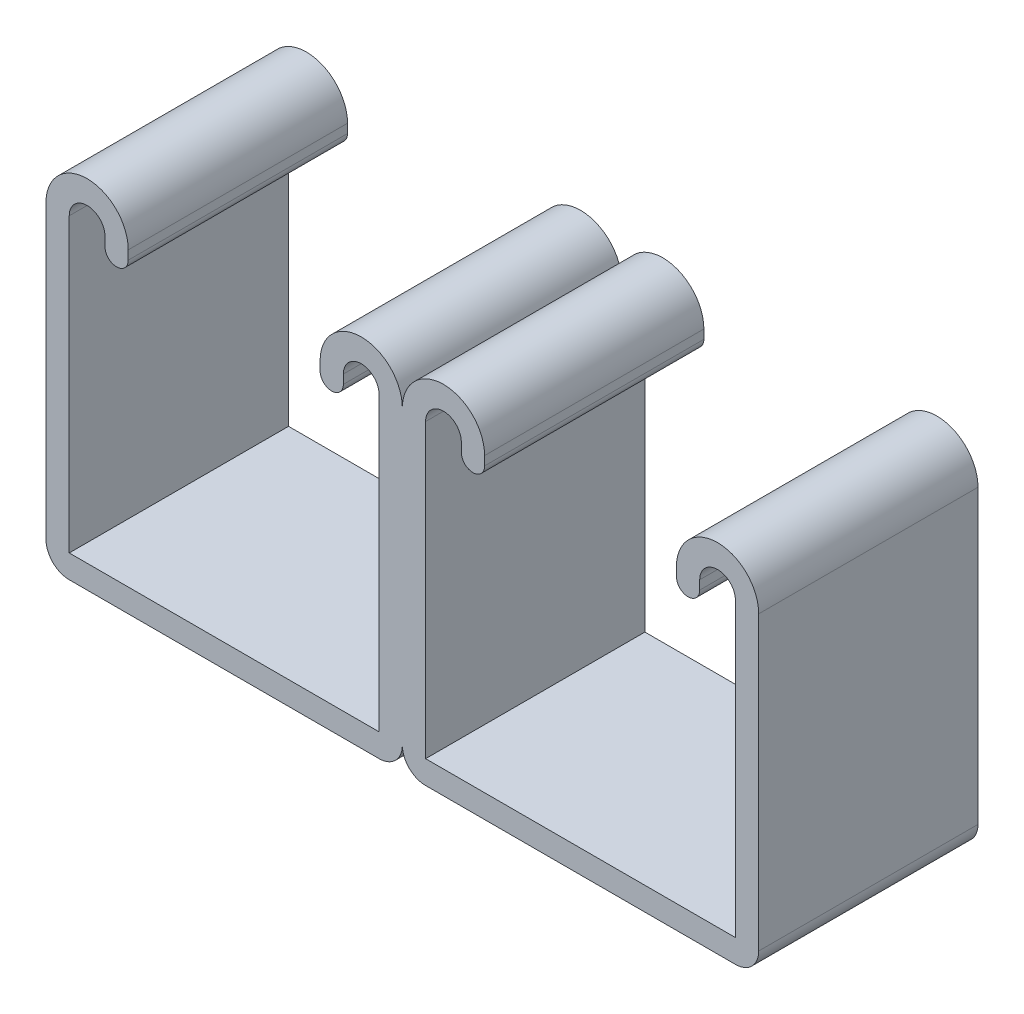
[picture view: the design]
ISO-10303-21;
HEADER;
FILE_DESCRIPTION(('STEP AP214'),'2;1');
FILE_NAME('part.step','',(''),(''),'','','');
FILE_SCHEMA(('AUTOMOTIVE_DESIGN { 1 0 10303 214 1 1 1 1 }'));
ENDSEC;
DATA;
#1=APPLICATION_CONTEXT('core data for automotive mechanical design processes');
#2=APPLICATION_PROTOCOL_DEFINITION('international standard','automotive_design',2000,#1);
#3=PRODUCT_CONTEXT('',#1,'mechanical');
#4=PRODUCT('Part','Part','',(#3));
#5=PRODUCT_RELATED_PRODUCT_CATEGORY('part','',(#4));
#6=PRODUCT_DEFINITION_FORMATION('','',#4);
#7=PRODUCT_DEFINITION_CONTEXT('part definition',#1,'design');
#8=PRODUCT_DEFINITION('design','',#6,#7);
#9=PRODUCT_DEFINITION_SHAPE('','',#8);
#10=(LENGTH_UNIT() NAMED_UNIT(*) SI_UNIT(.MILLI.,.METRE.));
#11=(NAMED_UNIT(*) PLANE_ANGLE_UNIT() SI_UNIT($,.RADIAN.));
#12=(NAMED_UNIT(*) SI_UNIT($,.STERADIAN.) SOLID_ANGLE_UNIT());
#13=UNCERTAINTY_MEASURE_WITH_UNIT(LENGTH_MEASURE(1.E-05),#10,'distance_accuracy_value','');
#14=(GEOMETRIC_REPRESENTATION_CONTEXT(3) GLOBAL_UNCERTAINTY_ASSIGNED_CONTEXT((#13)) GLOBAL_UNIT_ASSIGNED_CONTEXT((#10,
#11,#12)) REPRESENTATION_CONTEXT('',''));
#15=CARTESIAN_POINT('',(0.,0.,0.));
#16=DIRECTION('',(0.,0.,1.));
#17=DIRECTION('',(1.,0.,0.));
#18=AXIS2_PLACEMENT_3D('',#15,#16,#17);
#19=CARTESIAN_POINT('',(-36.5125,18.4785,12.7));
#20=DIRECTION('',(0.,0.,-1.));
#21=DIRECTION('',(-1.,0.,0.));
#22=AXIS2_PLACEMENT_3D('',#19,#20,#21);
#23=CYLINDRICAL_SURFACE('',#22,4.7625);
#24=CARTESIAN_POINT('',(-36.5125,18.4785,-12.7));
#25=DIRECTION('',(0.,0.,1.));
#26=DIRECTION('',(-1.,0.,0.));
#27=AXIS2_PLACEMENT_3D('',#24,#25,#26);
#28=CIRCLE('',#27,4.7625);
#29=CARTESIAN_POINT('',(-31.75,18.4785,-12.7));
#30=VERTEX_POINT('',#29);
#31=CARTESIAN_POINT('',(-41.275,18.4785,-12.7));
#32=VERTEX_POINT('',#31);
#33=EDGE_CURVE('E190',#30,#32,#28,.T.);
#34=ORIENTED_EDGE('',*,*,#33,.T.);
#35=DIRECTION('',(0.,0.,-1.));
#36=VECTOR('',#35,1.);
#37=CARTESIAN_POINT('',(-41.275,18.4785,12.7));
#38=LINE('',#37,#36);
#39=CARTESIAN_POINT('',(-41.275,18.4785,12.7));
#40=VERTEX_POINT('',#39);
#41=EDGE_CURVE('E11',#40,#32,#38,.T.);
#42=ORIENTED_EDGE('',*,*,#41,.F.);
#43=CARTESIAN_POINT('',(-36.5125,18.4785,12.7));
#44=DIRECTION('',(0.,0.,1.));
#45=DIRECTION('',(-1.,0.,0.));
#46=AXIS2_PLACEMENT_3D('',#43,#44,#45);
#47=CIRCLE('',#46,4.7625);
#48=CARTESIAN_POINT('',(-31.75,18.4785,12.7));
#49=VERTEX_POINT('',#48);
#50=EDGE_CURVE('E223',#49,#40,#47,.T.);
#51=ORIENTED_EDGE('',*,*,#50,.F.);
#52=DIRECTION('',(0.,0.,-1.));
#53=VECTOR('',#52,1.);
#54=CARTESIAN_POINT('',(-31.75,18.4785,12.7));
#55=LINE('',#54,#53);
#56=EDGE_CURVE('E186',#49,#30,#55,.T.);
#57=ORIENTED_EDGE('',*,*,#56,.T.);
#58=EDGE_LOOP('',(#34,#42,#51,#57));
#59=FACE_BOUND('',#58,.T.);
#60=ADVANCED_FACE('F33',(#59),#23,.T.);
#61=CARTESIAN_POINT('',(-41.275,18.4785,12.7));
#62=DIRECTION('',(1.,0.,0.));
#63=DIRECTION('',(0.,1.,0.));
#64=AXIS2_PLACEMENT_3D('',#61,#62,#63);
#65=PLANE('',#64);
#66=DIRECTION('',(0.,-1.,0.));
#67=VECTOR('',#66,1.);
#68=CARTESIAN_POINT('',(-41.275,18.4785,-12.7));
#69=LINE('',#68,#67);
#70=CARTESIAN_POINT('',(-41.275,-15.3416,-12.7));
#71=VERTEX_POINT('',#70);
#72=EDGE_CURVE('E193',#32,#71,#69,.T.);
#73=ORIENTED_EDGE('',*,*,#72,.T.);
#74=DIRECTION('',(0.,0.,-1.));
#75=VECTOR('',#74,1.);
#76=CARTESIAN_POINT('',(-41.275,-15.3416,12.7));
#77=LINE('',#76,#75);
#78=CARTESIAN_POINT('',(-41.275,-15.3416,12.7));
#79=VERTEX_POINT('',#78);
#80=EDGE_CURVE('E41',#79,#71,#77,.T.);
#81=ORIENTED_EDGE('',*,*,#80,.F.);
#82=DIRECTION('',(0.,-1.,0.));
#83=VECTOR('',#82,1.);
#84=CARTESIAN_POINT('',(-41.275,18.4785,12.7));
#85=LINE('',#84,#83);
#86=EDGE_CURVE('E120',#40,#79,#85,.T.);
#87=ORIENTED_EDGE('',*,*,#86,.F.);
#88=ORIENTED_EDGE('',*,*,#41,.T.);
#89=EDGE_LOOP('',(#73,#81,#87,#88));
#90=FACE_BOUND('',#89,.T.);
#91=ADVANCED_FACE('F330',(#90),#65,.F.);
#92=CARTESIAN_POINT('',(-38.5826,-15.3416,12.7));
#93=DIRECTION('',(0.,0.,-1.));
#94=DIRECTION('',(-1.,0.,0.));
#95=AXIS2_PLACEMENT_3D('',#92,#93,#94);
#96=CYLINDRICAL_SURFACE('',#95,2.6924);
#97=CARTESIAN_POINT('',(-38.5826,-15.3416,-12.7));
#98=DIRECTION('',(0.,0.,1.));
#99=DIRECTION('',(-1.,0.,0.));
#100=AXIS2_PLACEMENT_3D('',#97,#98,#99);
#101=CIRCLE('',#100,2.6924);
#102=CARTESIAN_POINT('',(-38.5826,-18.034,-12.7));
#103=VERTEX_POINT('',#102);
#104=EDGE_CURVE('E196',#71,#103,#101,.T.);
#105=ORIENTED_EDGE('',*,*,#104,.T.);
#106=DIRECTION('',(0.,0.,-1.));
#107=VECTOR('',#106,1.);
#108=CARTESIAN_POINT('',(-38.5826,-18.034,12.7));
#109=LINE('',#108,#107);
#110=CARTESIAN_POINT('',(-38.5826,-18.034,12.7));
#111=VERTEX_POINT('',#110);
#112=EDGE_CURVE('E260',#111,#103,#109,.T.);
#113=ORIENTED_EDGE('',*,*,#112,.F.);
#114=CARTESIAN_POINT('',(-38.5826,-15.3416,12.7));
#115=DIRECTION('',(0.,0.,1.));
#116=DIRECTION('',(-1.,0.,0.));
#117=AXIS2_PLACEMENT_3D('',#114,#115,#116);
#118=CIRCLE('',#117,2.6924);
#119=EDGE_CURVE('E268',#79,#111,#118,.T.);
#120=ORIENTED_EDGE('',*,*,#119,.F.);
#121=ORIENTED_EDGE('',*,*,#80,.T.);
#122=EDGE_LOOP('',(#105,#113,#120,#121));
#123=FACE_BOUND('',#122,.T.);
#124=ADVANCED_FACE('F266',(#123),#96,.T.);
#125=CARTESIAN_POINT('',(-38.5826,-18.034,12.7));
#126=DIRECTION('',(0.,1.,0.));
#127=DIRECTION('',(0.,0.,1.));
#128=AXIS2_PLACEMENT_3D('',#125,#126,#127);
#129=PLANE('',#128);
#130=DIRECTION('',(1.,0.,0.));
#131=VECTOR('',#130,1.);
#132=CARTESIAN_POINT('',(-38.5826,-18.034,-12.7));
#133=LINE('',#132,#131);
#134=CARTESIAN_POINT('',(-2.6924,-18.034,-12.7));
#135=VERTEX_POINT('',#134);
#136=EDGE_CURVE('E198',#103,#135,#133,.T.);
#137=ORIENTED_EDGE('',*,*,#136,.T.);
#138=DIRECTION('',(0.,0.,-1.));
#139=VECTOR('',#138,1.);
#140=CARTESIAN_POINT('',(-2.6924,-18.034,12.7));
#141=LINE('',#140,#139);
#142=CARTESIAN_POINT('',(-2.6924,-18.034,12.7));
#143=VERTEX_POINT('',#142);
#144=EDGE_CURVE('E257',#143,#135,#141,.T.);
#145=ORIENTED_EDGE('',*,*,#144,.F.);
#146=DIRECTION('',(1.,0.,0.));
#147=VECTOR('',#146,1.);
#148=CARTESIAN_POINT('',(-38.5826,-18.034,12.7));
#149=LINE('',#148,#147);
#150=EDGE_CURVE('E287',#111,#143,#149,.T.);
#151=ORIENTED_EDGE('',*,*,#150,.F.);
#152=ORIENTED_EDGE('',*,*,#112,.T.);
#153=EDGE_LOOP('',(#137,#145,#151,#152));
#154=FACE_BOUND('',#153,.T.);
#155=ADVANCED_FACE('F277',(#154),#129,.F.);
#156=CARTESIAN_POINT('',(-2.6924,-15.3416,12.7));
#157=DIRECTION('',(0.,0.,-1.));
#158=DIRECTION('',(-1.,0.,0.));
#159=AXIS2_PLACEMENT_3D('',#156,#157,#158);
#160=CYLINDRICAL_SURFACE('',#159,2.6924);
#161=CARTESIAN_POINT('',(-2.6924,-15.3416,-12.7));
#162=DIRECTION('',(0.,0.,1.));
#163=DIRECTION('',(1.,0.,0.));
#164=AXIS2_PLACEMENT_3D('',#161,#162,#163);
#165=CIRCLE('',#164,2.6924);
#166=CARTESIAN_POINT('',(0.,-15.3416,-12.7));
#167=VERTEX_POINT('',#166);
#168=EDGE_CURVE('E200',#135,#167,#165,.T.);
#169=ORIENTED_EDGE('',*,*,#168,.T.);
#170=DIRECTION('',(0.,0.,-1.));
#171=VECTOR('',#170,1.);
#172=CARTESIAN_POINT('',(0.,-15.3416,12.7));
#173=LINE('',#172,#171);
#174=CARTESIAN_POINT('',(0.,-15.3416,12.7));
#175=VERTEX_POINT('',#174);
#176=EDGE_CURVE('E254',#175,#167,#173,.T.);
#177=ORIENTED_EDGE('',*,*,#176,.F.);
#178=CARTESIAN_POINT('',(-2.6924,-15.3416,12.7));
#179=DIRECTION('',(0.,0.,1.));
#180=DIRECTION('',(1.,0.,0.));
#181=AXIS2_PLACEMENT_3D('',#178,#179,#180);
#182=CIRCLE('',#181,2.6924);
#183=EDGE_CURVE('E283',#143,#175,#182,.T.);
#184=ORIENTED_EDGE('',*,*,#183,.F.);
#185=ORIENTED_EDGE('',*,*,#144,.T.);
#186=EDGE_LOOP('',(#169,#177,#184,#185));
#187=FACE_BOUND('',#186,.T.);
#188=ADVANCED_FACE('F281',(#187),#160,.T.);
#189=CARTESIAN_POINT('',(-4.7625,18.4785,12.7));
#190=DIRECTION('',(0.,0.,-1.));
#191=DIRECTION('',(-1.,0.,0.));
#192=AXIS2_PLACEMENT_3D('',#189,#190,#191);
#193=CYLINDRICAL_SURFACE('',#192,4.7625);
#194=CARTESIAN_POINT('',(-4.7625,18.4785,-12.7));
#195=DIRECTION('',(0.,0.,1.));
#196=DIRECTION('',(1.,0.,0.));
#197=AXIS2_PLACEMENT_3D('',#194,#195,#196);
#198=CIRCLE('',#197,4.7625);
#199=CARTESIAN_POINT('',(0.,18.4785,-12.7));
#200=VERTEX_POINT('',#199);
#201=CARTESIAN_POINT('',(-9.525,18.4785,-12.7));
#202=VERTEX_POINT('',#201);
#203=EDGE_CURVE('E202',#200,#202,#198,.T.);
#204=ORIENTED_EDGE('',*,*,#203,.T.);
#205=DIRECTION('',(0.,0.,-1.));
#206=VECTOR('',#205,1.);
#207=CARTESIAN_POINT('',(-9.525,18.4785,12.7));
#208=LINE('',#207,#206);
#209=CARTESIAN_POINT('',(-9.525,18.4785,12.7));
#210=VERTEX_POINT('',#209);
#211=EDGE_CURVE('E248',#210,#202,#208,.T.);
#212=ORIENTED_EDGE('',*,*,#211,.F.);
#213=CARTESIAN_POINT('',(-4.7625,18.4785,12.7));
#214=DIRECTION('',(0.,0.,1.));
#215=DIRECTION('',(1.,0.,0.));
#216=AXIS2_PLACEMENT_3D('',#213,#214,#215);
#217=CIRCLE('',#216,4.7625);
#218=CARTESIAN_POINT('',(0.,18.4785,12.7));
#219=VERTEX_POINT('',#218);
#220=EDGE_CURVE('E286',#219,#210,#217,.T.);
#221=ORIENTED_EDGE('',*,*,#220,.F.);
#222=DIRECTION('',(0.,0.,-1.));
#223=VECTOR('',#222,1.);
#224=CARTESIAN_POINT('',(0.,18.4785,12.7));
#225=LINE('',#224,#223);
#226=EDGE_CURVE('E251',#219,#200,#225,.T.);
#227=ORIENTED_EDGE('',*,*,#226,.T.);
#228=EDGE_LOOP('',(#204,#212,#221,#227));
#229=FACE_BOUND('',#228,.T.);
#230=ADVANCED_FACE('F343',(#229),#193,.T.);
#231=CARTESIAN_POINT('',(-9.525,18.4785,12.7));
#232=DIRECTION('',(1.,0.,0.));
#233=DIRECTION('',(0.,1.,0.));
#234=AXIS2_PLACEMENT_3D('',#231,#232,#233);
#235=PLANE('',#234);
#236=DIRECTION('',(0.,-1.,0.));
#237=VECTOR('',#236,1.);
#238=CARTESIAN_POINT('',(-9.525,18.4785,-12.7));
#239=LINE('',#238,#237);
#240=CARTESIAN_POINT('',(-9.525,17.44345,-12.7));
#241=VERTEX_POINT('',#240);
#242=EDGE_CURVE('E204',#202,#241,#239,.T.);
#243=ORIENTED_EDGE('',*,*,#242,.T.);
#244=DIRECTION('',(0.,0.,-1.));
#245=VECTOR('',#244,1.);
#246=CARTESIAN_POINT('',(-9.525,17.44345,12.7));
#247=LINE('',#246,#245);
#248=CARTESIAN_POINT('',(-9.525,17.44345,12.7));
#249=VERTEX_POINT('',#248);
#250=EDGE_CURVE('E245',#249,#241,#247,.T.);
#251=ORIENTED_EDGE('',*,*,#250,.F.);
#252=DIRECTION('',(0.,-1.,0.));
#253=VECTOR('',#252,1.);
#254=CARTESIAN_POINT('',(-9.525,18.4785,12.7));
#255=LINE('',#254,#253);
#256=EDGE_CURVE('E289',#210,#249,#255,.T.);
#257=ORIENTED_EDGE('',*,*,#256,.F.);
#258=ORIENTED_EDGE('',*,*,#211,.T.);
#259=EDGE_LOOP('',(#243,#251,#257,#258));
#260=FACE_BOUND('',#259,.T.);
#261=ADVANCED_FACE('F346',(#260),#235,.F.);
#262=CARTESIAN_POINT('',(-8.1788,17.44345,12.7));
#263=DIRECTION('',(0.,0.,-1.));
#264=DIRECTION('',(-1.,0.,0.));
#265=AXIS2_PLACEMENT_3D('',#262,#263,#264);
#266=CYLINDRICAL_SURFACE('',#265,1.3462);
#267=CARTESIAN_POINT('',(-8.1788,17.44345,-12.7));
#268=DIRECTION('',(0.,0.,1.));
#269=DIRECTION('',(1.,0.,0.));
#270=AXIS2_PLACEMENT_3D('',#267,#268,#269);
#271=CIRCLE('',#270,1.3462);
#272=CARTESIAN_POINT('',(-6.8326,17.44345,-12.7));
#273=VERTEX_POINT('',#272);
#274=EDGE_CURVE('E206',#241,#273,#271,.T.);
#275=ORIENTED_EDGE('',*,*,#274,.T.);
#276=DIRECTION('',(0.,0.,-1.));
#277=VECTOR('',#276,1.);
#278=CARTESIAN_POINT('',(-6.8326,17.44345,12.7));
#279=LINE('',#278,#277);
#280=CARTESIAN_POINT('',(-6.8326,17.44345,12.7));
#281=VERTEX_POINT('',#280);
#282=EDGE_CURVE('E242',#281,#273,#279,.T.);
#283=ORIENTED_EDGE('',*,*,#282,.F.);
#284=CARTESIAN_POINT('',(-8.1788,17.44345,12.7));
#285=DIRECTION('',(0.,0.,1.));
#286=DIRECTION('',(1.,0.,0.));
#287=AXIS2_PLACEMENT_3D('',#284,#285,#286);
#288=CIRCLE('',#287,1.3462);
#289=EDGE_CURVE('E295',#249,#281,#288,.T.);
#290=ORIENTED_EDGE('',*,*,#289,.F.);
#291=ORIENTED_EDGE('',*,*,#250,.T.);
#292=EDGE_LOOP('',(#275,#283,#290,#291));
#293=FACE_BOUND('',#292,.T.);
#294=ADVANCED_FACE('F350',(#293),#266,.T.);
#295=CARTESIAN_POINT('',(-6.8326,18.4785,12.7));
#296=DIRECTION('',(-1.,0.,0.));
#297=DIRECTION('',(0.,0.,1.));
#298=AXIS2_PLACEMENT_3D('',#295,#296,#297);
#299=PLANE('',#298);
#300=DIRECTION('',(0.,1.,0.));
#301=VECTOR('',#300,1.);
#302=CARTESIAN_POINT('',(-6.8326,18.4785,-12.7));
#303=LINE('',#302,#301);
#304=CARTESIAN_POINT('',(-6.8326,18.4785,-12.7));
#305=VERTEX_POINT('',#304);
#306=EDGE_CURVE('E208',#273,#305,#303,.T.);
#307=ORIENTED_EDGE('',*,*,#306,.T.);
#308=DIRECTION('',(0.,0.,-1.));
#309=VECTOR('',#308,1.);
#310=CARTESIAN_POINT('',(-6.8326,18.4785,12.7));
#311=LINE('',#310,#309);
#312=CARTESIAN_POINT('',(-6.8326,18.4785,12.7));
#313=VERTEX_POINT('',#312);
#314=EDGE_CURVE('E239',#313,#305,#311,.T.);
#315=ORIENTED_EDGE('',*,*,#314,.F.);
#316=DIRECTION('',(0.,1.,0.));
#317=VECTOR('',#316,1.);
#318=CARTESIAN_POINT('',(-6.8326,18.4785,12.7));
#319=LINE('',#318,#317);
#320=EDGE_CURVE('E297',#281,#313,#319,.T.);
#321=ORIENTED_EDGE('',*,*,#320,.F.);
#322=ORIENTED_EDGE('',*,*,#282,.T.);
#323=EDGE_LOOP('',(#307,#315,#321,#322));
#324=FACE_BOUND('',#323,.T.);
#325=ADVANCED_FACE('F354',(#324),#299,.F.);
#326=CARTESIAN_POINT('',(-4.7625,18.4785,12.7));
#327=DIRECTION('',(0.,0.,-1.));
#328=DIRECTION('',(-1.,0.,0.));
#329=AXIS2_PLACEMENT_3D('',#326,#327,#328);
#330=CYLINDRICAL_SURFACE('',#329,2.0701);
#331=CARTESIAN_POINT('',(-4.7625,18.4785,-12.7));
#332=DIRECTION('',(0.,0.,-1.));
#333=DIRECTION('',(1.,0.,0.));
#334=AXIS2_PLACEMENT_3D('',#331,#332,#333);
#335=CIRCLE('',#334,2.0701);
#336=CARTESIAN_POINT('',(-2.6924,18.4785,-12.7));
#337=VERTEX_POINT('',#336);
#338=EDGE_CURVE('E210',#305,#337,#335,.T.);
#339=ORIENTED_EDGE('',*,*,#338,.T.);
#340=DIRECTION('',(0.,0.,-1.));
#341=VECTOR('',#340,1.);
#342=CARTESIAN_POINT('',(-2.6924,18.4785,12.7));
#343=LINE('',#342,#341);
#344=CARTESIAN_POINT('',(-2.6924,18.4785,12.7));
#345=VERTEX_POINT('',#344);
#346=EDGE_CURVE('E236',#345,#337,#343,.T.);
#347=ORIENTED_EDGE('',*,*,#346,.F.);
#348=CARTESIAN_POINT('',(-4.7625,18.4785,12.7));
#349=DIRECTION('',(0.,0.,-1.));
#350=DIRECTION('',(1.,0.,0.));
#351=AXIS2_PLACEMENT_3D('',#348,#349,#350);
#352=CIRCLE('',#351,2.0701);
#353=EDGE_CURVE('E299',#313,#345,#352,.T.);
#354=ORIENTED_EDGE('',*,*,#353,.F.);
#355=ORIENTED_EDGE('',*,*,#314,.T.);
#356=EDGE_LOOP('',(#339,#347,#354,#355));
#357=FACE_BOUND('',#356,.T.);
#358=ADVANCED_FACE('F358',(#357),#330,.F.);
#359=CARTESIAN_POINT('',(-2.6924,-15.3416,12.7));
#360=DIRECTION('',(1.,0.,0.));
#361=DIRECTION('',(0.,0.,-1.));
#362=AXIS2_PLACEMENT_3D('',#359,#360,#361);
#363=PLANE('',#362);
#364=DIRECTION('',(0.,-1.,0.));
#365=VECTOR('',#364,1.);
#366=CARTESIAN_POINT('',(-2.6924,-15.3416,-12.7));
#367=LINE('',#366,#365);
#368=CARTESIAN_POINT('',(-2.6924,-15.3416,-12.7));
#369=VERTEX_POINT('',#368);
#370=EDGE_CURVE('E212',#337,#369,#367,.T.);
#371=ORIENTED_EDGE('',*,*,#370,.T.);
#372=DIRECTION('',(0.,0.,-1.));
#373=VECTOR('',#372,1.);
#374=CARTESIAN_POINT('',(-2.6924,-15.3416,12.7));
#375=LINE('',#374,#373);
#376=CARTESIAN_POINT('',(-2.6924,-15.3416,12.7));
#377=VERTEX_POINT('',#376);
#378=EDGE_CURVE('E233',#377,#369,#375,.T.);
#379=ORIENTED_EDGE('',*,*,#378,.F.);
#380=DIRECTION('',(0.,-1.,0.));
#381=VECTOR('',#380,1.);
#382=CARTESIAN_POINT('',(-2.6924,-15.3416,12.7));
#383=LINE('',#382,#381);
#384=EDGE_CURVE('E301',#345,#377,#383,.T.);
#385=ORIENTED_EDGE('',*,*,#384,.F.);
#386=ORIENTED_EDGE('',*,*,#346,.T.);
#387=EDGE_LOOP('',(#371,#379,#385,#386));
#388=FACE_BOUND('',#387,.T.);
#389=ADVANCED_FACE('F362',(#388),#363,.F.);
#390=CARTESIAN_POINT('',(-38.5826,-15.3416,12.7));
#391=DIRECTION('',(0.,-1.,0.));
#392=DIRECTION('',(0.,0.,-1.));
#393=AXIS2_PLACEMENT_3D('',#390,#391,#392);
#394=PLANE('',#393);
#395=DIRECTION('',(-1.,0.,0.));
#396=VECTOR('',#395,1.);
#397=CARTESIAN_POINT('',(-38.5826,-15.3416,-12.7));
#398=LINE('',#397,#396);
#399=CARTESIAN_POINT('',(-38.5826,-15.3416,-12.7));
#400=VERTEX_POINT('',#399);
#401=EDGE_CURVE('E214',#369,#400,#398,.T.);
#402=ORIENTED_EDGE('',*,*,#401,.T.);
#403=DIRECTION('',(0.,0.,-1.));
#404=VECTOR('',#403,1.);
#405=CARTESIAN_POINT('',(-38.5826,-15.3416,12.7));
#406=LINE('',#405,#404);
#407=CARTESIAN_POINT('',(-38.5826,-15.3416,12.7));
#408=VERTEX_POINT('',#407);
#409=EDGE_CURVE('E230',#408,#400,#406,.T.);
#410=ORIENTED_EDGE('',*,*,#409,.F.);
#411=DIRECTION('',(-1.,0.,0.));
#412=VECTOR('',#411,1.);
#413=CARTESIAN_POINT('',(-38.5826,-15.3416,12.7));
#414=LINE('',#413,#412);
#415=EDGE_CURVE('E303',#377,#408,#414,.T.);
#416=ORIENTED_EDGE('',*,*,#415,.F.);
#417=ORIENTED_EDGE('',*,*,#378,.T.);
#418=EDGE_LOOP('',(#402,#410,#416,#417));
#419=FACE_BOUND('',#418,.T.);
#420=ADVANCED_FACE('F366',(#419),#394,.F.);
#421=CARTESIAN_POINT('',(-38.5826,18.4785,12.7));
#422=DIRECTION('',(-1.,0.,0.));
#423=DIRECTION('',(0.,-1.,0.));
#424=AXIS2_PLACEMENT_3D('',#421,#422,#423);
#425=PLANE('',#424);
#426=DIRECTION('',(0.,1.,0.));
#427=VECTOR('',#426,1.);
#428=CARTESIAN_POINT('',(-38.5826,18.4785,-12.7));
#429=LINE('',#428,#427);
#430=CARTESIAN_POINT('',(-38.5826,18.4785,-12.7));
#431=VERTEX_POINT('',#430);
#432=EDGE_CURVE('E216',#400,#431,#429,.T.);
#433=ORIENTED_EDGE('',*,*,#432,.T.);
#434=DIRECTION('',(0.,0.,-1.));
#435=VECTOR('',#434,1.);
#436=CARTESIAN_POINT('',(-38.5826,18.4785,12.7));
#437=LINE('',#436,#435);
#438=CARTESIAN_POINT('',(-38.5826,18.4785,12.7));
#439=VERTEX_POINT('',#438);
#440=EDGE_CURVE('E227',#439,#431,#437,.T.);
#441=ORIENTED_EDGE('',*,*,#440,.F.);
#442=DIRECTION('',(0.,1.,0.));
#443=VECTOR('',#442,1.);
#444=CARTESIAN_POINT('',(-38.5826,18.4785,12.7));
#445=LINE('',#444,#443);
#446=EDGE_CURVE('E305',#408,#439,#445,.T.);
#447=ORIENTED_EDGE('',*,*,#446,.F.);
#448=ORIENTED_EDGE('',*,*,#409,.T.);
#449=EDGE_LOOP('',(#433,#441,#447,#448));
#450=FACE_BOUND('',#449,.T.);
#451=ADVANCED_FACE('F311',(#450),#425,.F.);
#452=CARTESIAN_POINT('',(-36.5125,18.4785,12.7));
#453=DIRECTION('',(0.,0.,-1.));
#454=DIRECTION('',(-1.,0.,0.));
#455=AXIS2_PLACEMENT_3D('',#452,#453,#454);
#456=CYLINDRICAL_SURFACE('',#455,2.07010000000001);
#457=CARTESIAN_POINT('',(-36.5125,18.4785,-12.7));
#458=DIRECTION('',(0.,0.,-1.));
#459=DIRECTION('',(-1.,0.,0.));
#460=AXIS2_PLACEMENT_3D('',#457,#458,#459);
#461=CIRCLE('',#460,2.07010000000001);
#462=CARTESIAN_POINT('',(-34.4424,18.4785,-12.7));
#463=VERTEX_POINT('',#462);
#464=EDGE_CURVE('E218',#431,#463,#461,.T.);
#465=ORIENTED_EDGE('',*,*,#464,.T.);
#466=DIRECTION('',(0.,0.,-1.));
#467=VECTOR('',#466,1.);
#468=CARTESIAN_POINT('',(-34.4424,18.4785,12.7));
#469=LINE('',#468,#467);
#470=CARTESIAN_POINT('',(-34.4424,18.4785,12.7));
#471=VERTEX_POINT('',#470);
#472=EDGE_CURVE('E181',#471,#463,#469,.T.);
#473=ORIENTED_EDGE('',*,*,#472,.F.);
#474=CARTESIAN_POINT('',(-36.5125,18.4785,12.7));
#475=DIRECTION('',(0.,0.,-1.));
#476=DIRECTION('',(-1.,0.,0.));
#477=AXIS2_PLACEMENT_3D('',#474,#475,#476);
#478=CIRCLE('',#477,2.07010000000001);
#479=EDGE_CURVE('E172',#439,#471,#478,.T.);
#480=ORIENTED_EDGE('',*,*,#479,.F.);
#481=ORIENTED_EDGE('',*,*,#440,.T.);
#482=EDGE_LOOP('',(#465,#473,#480,#481));
#483=FACE_BOUND('',#482,.T.);
#484=ADVANCED_FACE('F315',(#483),#456,.F.);
#485=CARTESIAN_POINT('',(-34.4424,18.4785,12.7));
#486=DIRECTION('',(1.,0.,0.));
#487=DIRECTION('',(0.,0.,-1.));
#488=AXIS2_PLACEMENT_3D('',#485,#486,#487);
#489=PLANE('',#488);
#490=DIRECTION('',(0.,-1.,0.));
#491=VECTOR('',#490,1.);
#492=CARTESIAN_POINT('',(-34.4424,18.4785,-12.7));
#493=LINE('',#492,#491);
#494=CARTESIAN_POINT('',(-34.4424,17.44345,-12.7));
#495=VERTEX_POINT('',#494);
#496=EDGE_CURVE('E180',#463,#495,#493,.T.);
#497=ORIENTED_EDGE('',*,*,#496,.T.);
#498=DIRECTION('',(0.,0.,-1.));
#499=VECTOR('',#498,1.);
#500=CARTESIAN_POINT('',(-34.4424,17.44345,12.7));
#501=LINE('',#500,#499);
#502=CARTESIAN_POINT('',(-34.4424,17.44345,12.7));
#503=VERTEX_POINT('',#502);
#504=EDGE_CURVE('E177',#503,#495,#501,.T.);
#505=ORIENTED_EDGE('',*,*,#504,.F.);
#506=DIRECTION('',(0.,-1.,0.));
#507=VECTOR('',#506,1.);
#508=CARTESIAN_POINT('',(-34.4424,18.4785,12.7));
#509=LINE('',#508,#507);
#510=EDGE_CURVE('E166',#471,#503,#509,.T.);
#511=ORIENTED_EDGE('',*,*,#510,.F.);
#512=ORIENTED_EDGE('',*,*,#472,.T.);
#513=EDGE_LOOP('',(#497,#505,#511,#512));
#514=FACE_BOUND('',#513,.T.);
#515=ADVANCED_FACE('F178',(#514),#489,.F.);
#516=CARTESIAN_POINT('',(-33.0962,17.44345,12.7));
#517=DIRECTION('',(0.,0.,-1.));
#518=DIRECTION('',(-1.,0.,0.));
#519=AXIS2_PLACEMENT_3D('',#516,#517,#518);
#520=CYLINDRICAL_SURFACE('',#519,1.3462);
#521=CARTESIAN_POINT('',(-33.0962,17.44345,-12.7));
#522=DIRECTION('',(0.,0.,1.));
#523=DIRECTION('',(-1.,0.,0.));
#524=AXIS2_PLACEMENT_3D('',#521,#522,#523);
#525=CIRCLE('',#524,1.3462);
#526=CARTESIAN_POINT('',(-31.75,17.44345,-12.7));
#527=VERTEX_POINT('',#526);
#528=EDGE_CURVE('E106',#495,#527,#525,.T.);
#529=ORIENTED_EDGE('',*,*,#528,.T.);
#530=DIRECTION('',(0.,0.,-1.));
#531=VECTOR('',#530,1.);
#532=CARTESIAN_POINT('',(-31.75,17.44345,12.7));
#533=LINE('',#532,#531);
#534=CARTESIAN_POINT('',(-31.75,17.44345,12.7));
#535=VERTEX_POINT('',#534);
#536=EDGE_CURVE('E182',#535,#527,#533,.T.);
#537=ORIENTED_EDGE('',*,*,#536,.F.);
#538=CARTESIAN_POINT('',(-33.0962,17.44345,12.7));
#539=DIRECTION('',(0.,0.,1.));
#540=DIRECTION('',(-1.,0.,0.));
#541=AXIS2_PLACEMENT_3D('',#538,#539,#540);
#542=CIRCLE('',#541,1.3462);
#543=EDGE_CURVE('E170',#503,#535,#542,.T.);
#544=ORIENTED_EDGE('',*,*,#543,.F.);
#545=ORIENTED_EDGE('',*,*,#504,.T.);
#546=EDGE_LOOP('',(#529,#537,#544,#545));
#547=FACE_BOUND('',#546,.T.);
#548=ADVANCED_FACE('F184',(#547),#520,.T.);
#549=CARTESIAN_POINT('',(-31.75,18.4785,12.7));
#550=DIRECTION('',(-1.,0.,0.));
#551=DIRECTION('',(0.,0.,1.));
#552=AXIS2_PLACEMENT_3D('',#549,#550,#551);
#553=PLANE('',#552);
#554=DIRECTION('',(0.,1.,0.));
#555=VECTOR('',#554,1.);
#556=CARTESIAN_POINT('',(-31.75,18.4785,-12.7));
#557=LINE('',#556,#555);
#558=EDGE_CURVE('E112',#527,#30,#557,.T.);
#559=ORIENTED_EDGE('',*,*,#558,.T.);
#560=ORIENTED_EDGE('',*,*,#56,.F.);
#561=DIRECTION('',(0.,1.,0.));
#562=VECTOR('',#561,1.);
#563=CARTESIAN_POINT('',(-31.75,18.4785,12.7));
#564=LINE('',#563,#562);
#565=EDGE_CURVE('E49',#535,#49,#564,.T.);
#566=ORIENTED_EDGE('',*,*,#565,.F.);
#567=ORIENTED_EDGE('',*,*,#536,.T.);
#568=EDGE_LOOP('',(#559,#560,#566,#567));
#569=FACE_BOUND('',#568,.T.);
#570=ADVANCED_FACE('F319',(#569),#553,.F.);
#571=CARTESIAN_POINT('',(-36.5125,18.4785,12.7));
#572=DIRECTION('',(0.,0.,-1.));
#573=DIRECTION('',(-1.,0.,0.));
#574=AXIS2_PLACEMENT_3D('',#571,#572,#573);
#575=PLANE('',#574);
#576=ORIENTED_EDGE('',*,*,#50,.T.);
#577=ORIENTED_EDGE('',*,*,#86,.T.);
#578=ORIENTED_EDGE('',*,*,#119,.T.);
#579=ORIENTED_EDGE('',*,*,#150,.T.);
#580=ORIENTED_EDGE('',*,*,#183,.T.);
#581=CARTESIAN_POINT('',(2.6924,-15.3416,12.7));
#582=DIRECTION('',(0.,0.,1.));
#583=DIRECTION('',(-1.,0.,0.));
#584=AXIS2_PLACEMENT_3D('',#581,#582,#583);
#585=CIRCLE('',#584,2.6924);
#586=CARTESIAN_POINT('',(2.6924,-18.034,12.7));
#587=VERTEX_POINT('',#586);
#588=EDGE_CURVE('E830',#175,#587,#585,.T.);
#589=ORIENTED_EDGE('',*,*,#588,.T.);
#590=DIRECTION('',(1.,0.,0.));
#591=VECTOR('',#590,1.);
#592=CARTESIAN_POINT('',(2.6924,-18.034,12.7));
#593=LINE('',#592,#591);
#594=CARTESIAN_POINT('',(38.5826,-18.034,12.7));
#595=VERTEX_POINT('',#594);
#596=EDGE_CURVE('E716',#587,#595,#593,.T.);
#597=ORIENTED_EDGE('',*,*,#596,.T.);
#598=CARTESIAN_POINT('',(38.5826,-15.3416,12.7));
#599=DIRECTION('',(0.,0.,1.));
#600=DIRECTION('',(1.,0.,0.));
#601=AXIS2_PLACEMENT_3D('',#598,#599,#600);
#602=CIRCLE('',#601,2.6924);
#603=CARTESIAN_POINT('',(41.275,-15.3416,12.7));
#604=VERTEX_POINT('',#603);
#605=EDGE_CURVE('E739',#595,#604,#602,.T.);
#606=ORIENTED_EDGE('',*,*,#605,.T.);
#607=DIRECTION('',(0.,1.,0.));
#608=VECTOR('',#607,1.);
#609=CARTESIAN_POINT('',(41.275,-15.3416,12.7));
#610=LINE('',#609,#608);
#611=CARTESIAN_POINT('',(41.275,18.4785,12.7));
#612=VERTEX_POINT('',#611);
#613=EDGE_CURVE('E731',#604,#612,#610,.T.);
#614=ORIENTED_EDGE('',*,*,#613,.T.);
#615=CARTESIAN_POINT('',(36.5125,18.4785,12.7));
#616=DIRECTION('',(0.,0.,1.));
#617=DIRECTION('',(1.,0.,0.));
#618=AXIS2_PLACEMENT_3D('',#615,#616,#617);
#619=CIRCLE('',#618,4.7625);
#620=CARTESIAN_POINT('',(31.75,18.4785,12.7));
#621=VERTEX_POINT('',#620);
#622=EDGE_CURVE('E738',#612,#621,#619,.T.);
#623=ORIENTED_EDGE('',*,*,#622,.T.);
#624=DIRECTION('',(0.,-1.,0.));
#625=VECTOR('',#624,1.);
#626=CARTESIAN_POINT('',(31.75,18.4785,12.7));
#627=LINE('',#626,#625);
#628=CARTESIAN_POINT('',(31.75,17.44345,12.7));
#629=VERTEX_POINT('',#628);
#630=EDGE_CURVE('E741',#621,#629,#627,.T.);
#631=ORIENTED_EDGE('',*,*,#630,.T.);
#632=CARTESIAN_POINT('',(33.0962,17.44345,12.7));
#633=DIRECTION('',(0.,0.,1.));
#634=DIRECTION('',(1.,0.,0.));
#635=AXIS2_PLACEMENT_3D('',#632,#633,#634);
#636=CIRCLE('',#635,1.3462);
#637=CARTESIAN_POINT('',(34.4424,17.44345,12.7));
#638=VERTEX_POINT('',#637);
#639=EDGE_CURVE('E748',#629,#638,#636,.T.);
#640=ORIENTED_EDGE('',*,*,#639,.T.);
#641=DIRECTION('',(0.,1.,0.));
#642=VECTOR('',#641,1.);
#643=CARTESIAN_POINT('',(34.4424,18.4785,12.7));
#644=LINE('',#643,#642);
#645=CARTESIAN_POINT('',(34.4424,18.4785,12.7));
#646=VERTEX_POINT('',#645);
#647=EDGE_CURVE('E751',#638,#646,#644,.T.);
#648=ORIENTED_EDGE('',*,*,#647,.T.);
#649=CARTESIAN_POINT('',(36.5125,18.4785,12.7));
#650=DIRECTION('',(0.,0.,-1.));
#651=DIRECTION('',(1.,0.,0.));
#652=AXIS2_PLACEMENT_3D('',#649,#650,#651);
#653=CIRCLE('',#652,2.0701);
#654=CARTESIAN_POINT('',(38.5826,18.4785,12.7));
#655=VERTEX_POINT('',#654);
#656=EDGE_CURVE('E754',#646,#655,#653,.T.);
#657=ORIENTED_EDGE('',*,*,#656,.T.);
#658=DIRECTION('',(0.,-1.,0.));
#659=VECTOR('',#658,1.);
#660=CARTESIAN_POINT('',(38.5826,-15.3416,12.7));
#661=LINE('',#660,#659);
#662=CARTESIAN_POINT('',(38.5826,-15.3416,12.7));
#663=VERTEX_POINT('',#662);
#664=EDGE_CURVE('E757',#655,#663,#661,.T.);
#665=ORIENTED_EDGE('',*,*,#664,.T.);
#666=DIRECTION('',(-1.,0.,0.));
#667=VECTOR('',#666,1.);
#668=CARTESIAN_POINT('',(2.6924,-15.3416,12.7));
#669=LINE('',#668,#667);
#670=CARTESIAN_POINT('',(2.6924,-15.3416,12.7));
#671=VERTEX_POINT('',#670);
#672=EDGE_CURVE('E760',#663,#671,#669,.T.);
#673=ORIENTED_EDGE('',*,*,#672,.T.);
#674=DIRECTION('',(0.,1.,0.));
#675=VECTOR('',#674,1.);
#676=CARTESIAN_POINT('',(2.69239999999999,18.4785,12.7));
#677=LINE('',#676,#675);
#678=CARTESIAN_POINT('',(2.69239999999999,18.4785,12.7));
#679=VERTEX_POINT('',#678);
#680=EDGE_CURVE('E763',#671,#679,#677,.T.);
#681=ORIENTED_EDGE('',*,*,#680,.T.);
#682=CARTESIAN_POINT('',(4.7625,18.4785,12.7));
#683=DIRECTION('',(0.,0.,-1.));
#684=DIRECTION('',(-1.,0.,0.));
#685=AXIS2_PLACEMENT_3D('',#682,#683,#684);
#686=CIRCLE('',#685,2.07010000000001);
#687=CARTESIAN_POINT('',(6.8326,18.4785,12.7));
#688=VERTEX_POINT('',#687);
#689=EDGE_CURVE('E766',#679,#688,#686,.T.);
#690=ORIENTED_EDGE('',*,*,#689,.T.);
#691=DIRECTION('',(0.,-1.,0.));
#692=VECTOR('',#691,1.);
#693=CARTESIAN_POINT('',(6.8326,18.4785,12.7));
#694=LINE('',#693,#692);
#695=CARTESIAN_POINT('',(6.8326,17.44345,12.7));
#696=VERTEX_POINT('',#695);
#697=EDGE_CURVE('E769',#688,#696,#694,.T.);
#698=ORIENTED_EDGE('',*,*,#697,.T.);
#699=CARTESIAN_POINT('',(8.1788,17.44345,12.7));
#700=DIRECTION('',(0.,0.,1.));
#701=DIRECTION('',(-1.,0.,0.));
#702=AXIS2_PLACEMENT_3D('',#699,#700,#701);
#703=CIRCLE('',#702,1.3462);
#704=CARTESIAN_POINT('',(9.525,17.44345,12.7));
#705=VERTEX_POINT('',#704);
#706=EDGE_CURVE('E771',#696,#705,#703,.T.);
#707=ORIENTED_EDGE('',*,*,#706,.T.);
#708=DIRECTION('',(0.,1.,0.));
#709=VECTOR('',#708,1.);
#710=CARTESIAN_POINT('',(9.525,18.4785,12.7));
#711=LINE('',#710,#709);
#712=CARTESIAN_POINT('',(9.525,18.4785,12.7));
#713=VERTEX_POINT('',#712);
#714=EDGE_CURVE('E614',#705,#713,#711,.T.);
#715=ORIENTED_EDGE('',*,*,#714,.T.);
#716=CARTESIAN_POINT('',(4.7625,18.4785,12.7));
#717=DIRECTION('',(0.,0.,1.));
#718=DIRECTION('',(-1.,0.,0.));
#719=AXIS2_PLACEMENT_3D('',#716,#717,#718);
#720=CIRCLE('',#719,4.7625);
#721=EDGE_CURVE('E606',#713,#219,#720,.T.);
#722=ORIENTED_EDGE('',*,*,#721,.T.);
#723=ORIENTED_EDGE('',*,*,#220,.T.);
#724=ORIENTED_EDGE('',*,*,#256,.T.);
#725=ORIENTED_EDGE('',*,*,#289,.T.);
#726=ORIENTED_EDGE('',*,*,#320,.T.);
#727=ORIENTED_EDGE('',*,*,#353,.T.);
#728=ORIENTED_EDGE('',*,*,#384,.T.);
#729=ORIENTED_EDGE('',*,*,#415,.T.);
#730=ORIENTED_EDGE('',*,*,#446,.T.);
#731=ORIENTED_EDGE('',*,*,#479,.T.);
#732=ORIENTED_EDGE('',*,*,#510,.T.);
#733=ORIENTED_EDGE('',*,*,#543,.T.);
#734=ORIENTED_EDGE('',*,*,#565,.T.);
#735=EDGE_LOOP('',(#576,#577,#578,#579,#580,#589,#597,#606,#614,#623,#631,#640,#648,#657,#665,
#673,#681,#690,#698,#707,#715,#722,#723,#724,#725,#726,#727,#728,#729,#730,#731,#732,#733,#734));
#736=FACE_BOUND('',#735,.T.);
#737=ADVANCED_FACE('F168',(#736),#575,.F.);
#738=CARTESIAN_POINT('',(-36.5125,18.4785,-12.7));
#739=DIRECTION('',(0.,0.,-1.));
#740=DIRECTION('',(-1.,0.,0.));
#741=AXIS2_PLACEMENT_3D('',#738,#739,#740);
#742=PLANE('',#741);
#743=ORIENTED_EDGE('',*,*,#33,.F.);
#744=ORIENTED_EDGE('',*,*,#558,.F.);
#745=ORIENTED_EDGE('',*,*,#528,.F.);
#746=ORIENTED_EDGE('',*,*,#496,.F.);
#747=ORIENTED_EDGE('',*,*,#464,.F.);
#748=ORIENTED_EDGE('',*,*,#432,.F.);
#749=ORIENTED_EDGE('',*,*,#401,.F.);
#750=ORIENTED_EDGE('',*,*,#370,.F.);
#751=ORIENTED_EDGE('',*,*,#338,.F.);
#752=ORIENTED_EDGE('',*,*,#306,.F.);
#753=ORIENTED_EDGE('',*,*,#274,.F.);
#754=ORIENTED_EDGE('',*,*,#242,.F.);
#755=ORIENTED_EDGE('',*,*,#203,.F.);
#756=CARTESIAN_POINT('',(4.7625,18.4785,-12.7));
#757=DIRECTION('',(0.,0.,1.));
#758=DIRECTION('',(-1.,0.,0.));
#759=AXIS2_PLACEMENT_3D('',#756,#757,#758);
#760=CIRCLE('',#759,4.7625);
#761=CARTESIAN_POINT('',(9.525,18.4785,-12.7));
#762=VERTEX_POINT('',#761);
#763=EDGE_CURVE('E612',#762,#200,#760,.T.);
#764=ORIENTED_EDGE('',*,*,#763,.F.);
#765=DIRECTION('',(0.,1.,0.));
#766=VECTOR('',#765,1.);
#767=CARTESIAN_POINT('',(9.525,18.4785,-12.7));
#768=LINE('',#767,#766);
#769=CARTESIAN_POINT('',(9.525,17.44345,-12.7));
#770=VERTEX_POINT('',#769);
#771=EDGE_CURVE('E595',#770,#762,#768,.T.);
#772=ORIENTED_EDGE('',*,*,#771,.F.);
#773=CARTESIAN_POINT('',(8.1788,17.44345,-12.7));
#774=DIRECTION('',(0.,0.,1.));
#775=DIRECTION('',(-1.,0.,0.));
#776=AXIS2_PLACEMENT_3D('',#773,#774,#775);
#777=CIRCLE('',#776,1.3462);
#778=CARTESIAN_POINT('',(6.8326,17.44345,-12.7));
#779=VERTEX_POINT('',#778);
#780=EDGE_CURVE('E607',#779,#770,#777,.T.);
#781=ORIENTED_EDGE('',*,*,#780,.F.);
#782=DIRECTION('',(0.,-1.,0.));
#783=VECTOR('',#782,1.);
#784=CARTESIAN_POINT('',(6.8326,18.4785,-12.7));
#785=LINE('',#784,#783);
#786=CARTESIAN_POINT('',(6.8326,18.4785,-12.7));
#787=VERTEX_POINT('',#786);
#788=EDGE_CURVE('E661',#787,#779,#785,.T.);
#789=ORIENTED_EDGE('',*,*,#788,.F.);
#790=CARTESIAN_POINT('',(4.7625,18.4785,-12.7));
#791=DIRECTION('',(0.,0.,-1.));
#792=DIRECTION('',(-1.,0.,0.));
#793=AXIS2_PLACEMENT_3D('',#790,#791,#792);
#794=CIRCLE('',#793,2.07010000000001);
#795=CARTESIAN_POINT('',(2.69239999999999,18.4785,-12.7));
#796=VERTEX_POINT('',#795);
#797=EDGE_CURVE('E658',#796,#787,#794,.T.);
#798=ORIENTED_EDGE('',*,*,#797,.F.);
#799=DIRECTION('',(0.,1.,0.));
#800=VECTOR('',#799,1.);
#801=CARTESIAN_POINT('',(2.69239999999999,18.4785,-12.7));
#802=LINE('',#801,#800);
#803=CARTESIAN_POINT('',(2.6924,-15.3416,-12.7));
#804=VERTEX_POINT('',#803);
#805=EDGE_CURVE('E655',#804,#796,#802,.T.);
#806=ORIENTED_EDGE('',*,*,#805,.F.);
#807=DIRECTION('',(-1.,0.,0.));
#808=VECTOR('',#807,1.);
#809=CARTESIAN_POINT('',(2.6924,-15.3416,-12.7));
#810=LINE('',#809,#808);
#811=CARTESIAN_POINT('',(38.5826,-15.3416,-12.7));
#812=VERTEX_POINT('',#811);
#813=EDGE_CURVE('E652',#812,#804,#810,.T.);
#814=ORIENTED_EDGE('',*,*,#813,.F.);
#815=DIRECTION('',(0.,-1.,0.));
#816=VECTOR('',#815,1.);
#817=CARTESIAN_POINT('',(38.5826,-15.3416,-12.7));
#818=LINE('',#817,#816);
#819=CARTESIAN_POINT('',(38.5826,18.4785,-12.7));
#820=VERTEX_POINT('',#819);
#821=EDGE_CURVE('E649',#820,#812,#818,.T.);
#822=ORIENTED_EDGE('',*,*,#821,.F.);
#823=CARTESIAN_POINT('',(36.5125,18.4785,-12.7));
#824=DIRECTION('',(0.,0.,-1.));
#825=DIRECTION('',(1.,0.,0.));
#826=AXIS2_PLACEMENT_3D('',#823,#824,#825);
#827=CIRCLE('',#826,2.0701);
#828=CARTESIAN_POINT('',(34.4424,18.4785,-12.7));
#829=VERTEX_POINT('',#828);
#830=EDGE_CURVE('E646',#829,#820,#827,.T.);
#831=ORIENTED_EDGE('',*,*,#830,.F.);
#832=DIRECTION('',(0.,1.,0.));
#833=VECTOR('',#832,1.);
#834=CARTESIAN_POINT('',(34.4424,18.4785,-12.7));
#835=LINE('',#834,#833);
#836=CARTESIAN_POINT('',(34.4424,17.44345,-12.7));
#837=VERTEX_POINT('',#836);
#838=EDGE_CURVE('E643',#837,#829,#835,.T.);
#839=ORIENTED_EDGE('',*,*,#838,.F.);
#840=CARTESIAN_POINT('',(33.0962,17.44345,-12.7));
#841=DIRECTION('',(0.,0.,1.));
#842=DIRECTION('',(1.,0.,0.));
#843=AXIS2_PLACEMENT_3D('',#840,#841,#842);
#844=CIRCLE('',#843,1.3462);
#845=CARTESIAN_POINT('',(31.75,17.44345,-12.7));
#846=VERTEX_POINT('',#845);
#847=EDGE_CURVE('E640',#846,#837,#844,.T.);
#848=ORIENTED_EDGE('',*,*,#847,.F.);
#849=DIRECTION('',(0.,-1.,0.));
#850=VECTOR('',#849,1.);
#851=CARTESIAN_POINT('',(31.75,18.4785,-12.7));
#852=LINE('',#851,#850);
#853=CARTESIAN_POINT('',(31.75,18.4785,-12.7));
#854=VERTEX_POINT('',#853);
#855=EDGE_CURVE('E637',#854,#846,#852,.T.);
#856=ORIENTED_EDGE('',*,*,#855,.F.);
#857=CARTESIAN_POINT('',(36.5125,18.4785,-12.7));
#858=DIRECTION('',(0.,0.,1.));
#859=DIRECTION('',(1.,0.,0.));
#860=AXIS2_PLACEMENT_3D('',#857,#858,#859);
#861=CIRCLE('',#860,4.7625);
#862=CARTESIAN_POINT('',(41.275,18.4785,-12.7));
#863=VERTEX_POINT('',#862);
#864=EDGE_CURVE('E634',#863,#854,#861,.T.);
#865=ORIENTED_EDGE('',*,*,#864,.F.);
#866=DIRECTION('',(0.,1.,0.));
#867=VECTOR('',#866,1.);
#868=CARTESIAN_POINT('',(41.275,-15.3416,-12.7));
#869=LINE('',#868,#867);
#870=CARTESIAN_POINT('',(41.275,-15.3416,-12.7));
#871=VERTEX_POINT('',#870);
#872=EDGE_CURVE('E631',#871,#863,#869,.T.);
#873=ORIENTED_EDGE('',*,*,#872,.F.);
#874=CARTESIAN_POINT('',(38.5826,-15.3416,-12.7));
#875=DIRECTION('',(0.,0.,1.));
#876=DIRECTION('',(1.,0.,0.));
#877=AXIS2_PLACEMENT_3D('',#874,#875,#876);
#878=CIRCLE('',#877,2.6924);
#879=CARTESIAN_POINT('',(38.5826,-18.034,-12.7));
#880=VERTEX_POINT('',#879);
#881=EDGE_CURVE('E628',#880,#871,#878,.T.);
#882=ORIENTED_EDGE('',*,*,#881,.F.);
#883=DIRECTION('',(1.,0.,0.));
#884=VECTOR('',#883,1.);
#885=CARTESIAN_POINT('',(2.6924,-18.034,-12.7));
#886=LINE('',#885,#884);
#887=CARTESIAN_POINT('',(2.6924,-18.034,-12.7));
#888=VERTEX_POINT('',#887);
#889=EDGE_CURVE('E621',#888,#880,#886,.T.);
#890=ORIENTED_EDGE('',*,*,#889,.F.);
#891=CARTESIAN_POINT('',(2.6924,-15.3416,-12.7));
#892=DIRECTION('',(0.,0.,1.));
#893=DIRECTION('',(-1.,0.,0.));
#894=AXIS2_PLACEMENT_3D('',#891,#892,#893);
#895=CIRCLE('',#894,2.6924);
#896=EDGE_CURVE('E618',#167,#888,#895,.T.);
#897=ORIENTED_EDGE('',*,*,#896,.F.);
#898=ORIENTED_EDGE('',*,*,#168,.F.);
#899=ORIENTED_EDGE('',*,*,#136,.F.);
#900=ORIENTED_EDGE('',*,*,#104,.F.);
#901=ORIENTED_EDGE('',*,*,#72,.F.);
#902=EDGE_LOOP('',(#743,#744,#745,#746,#747,#748,#749,#750,#751,#752,#753,#754,#755,#764,#772,
#781,#789,#798,#806,#814,#822,#831,#839,#848,#856,#865,#873,#882,#890,#897,#898,#899,#900,#901));
#903=FACE_BOUND('',#902,.T.);
#904=ADVANCED_FACE('F272',(#903),#742,.T.);
#905=CARTESIAN_POINT('',(4.7625,18.4785,12.7));
#906=DIRECTION('',(0.,0.,-1.));
#907=DIRECTION('',(-1.,0.,0.));
#908=AXIS2_PLACEMENT_3D('',#905,#906,#907);
#909=CYLINDRICAL_SURFACE('',#908,4.7625);
#910=ORIENTED_EDGE('',*,*,#763,.T.);
#911=ORIENTED_EDGE('',*,*,#226,.F.);
#912=ORIENTED_EDGE('',*,*,#721,.F.);
#913=DIRECTION('',(0.,0.,-1.));
#914=VECTOR('',#913,1.);
#915=CARTESIAN_POINT('',(9.525,18.4785,12.7));
#916=LINE('',#915,#914);
#917=EDGE_CURVE('E598',#713,#762,#916,.T.);
#918=ORIENTED_EDGE('',*,*,#917,.T.);
#919=EDGE_LOOP('',(#910,#911,#912,#918));
#920=FACE_BOUND('',#919,.T.);
#921=ADVANCED_FACE('F419',(#920),#909,.T.);
#922=CARTESIAN_POINT('',(2.6924,-15.3416,12.7));
#923=DIRECTION('',(0.,0.,-1.));
#924=DIRECTION('',(-1.,0.,0.));
#925=AXIS2_PLACEMENT_3D('',#922,#923,#924);
#926=CYLINDRICAL_SURFACE('',#925,2.6924);
#927=ORIENTED_EDGE('',*,*,#896,.T.);
#928=DIRECTION('',(0.,0.,-1.));
#929=VECTOR('',#928,1.);
#930=CARTESIAN_POINT('',(2.6924,-18.034,12.7));
#931=LINE('',#930,#929);
#932=EDGE_CURVE('E194',#587,#888,#931,.T.);
#933=ORIENTED_EDGE('',*,*,#932,.F.);
#934=ORIENTED_EDGE('',*,*,#588,.F.);
#935=ORIENTED_EDGE('',*,*,#176,.T.);
#936=EDGE_LOOP('',(#927,#933,#934,#935));
#937=FACE_BOUND('',#936,.T.);
#938=ADVANCED_FACE('F427',(#937),#926,.T.);
#939=CARTESIAN_POINT('',(2.6924,-18.034,12.7));
#940=DIRECTION('',(0.,1.,0.));
#941=DIRECTION('',(0.,0.,1.));
#942=AXIS2_PLACEMENT_3D('',#939,#940,#941);
#943=PLANE('',#942);
#944=ORIENTED_EDGE('',*,*,#889,.T.);
#945=DIRECTION('',(0.,0.,-1.));
#946=VECTOR('',#945,1.);
#947=CARTESIAN_POINT('',(38.5826,-18.034,12.7));
#948=LINE('',#947,#946);
#949=EDGE_CURVE('E703',#595,#880,#948,.T.);
#950=ORIENTED_EDGE('',*,*,#949,.F.);
#951=ORIENTED_EDGE('',*,*,#596,.F.);
#952=ORIENTED_EDGE('',*,*,#932,.T.);
#953=EDGE_LOOP('',(#944,#950,#951,#952));
#954=FACE_BOUND('',#953,.T.);
#955=ADVANCED_FACE('F437',(#954),#943,.F.);
#956=CARTESIAN_POINT('',(38.5826,-15.3416,12.7));
#957=DIRECTION('',(0.,0.,-1.));
#958=DIRECTION('',(-1.,0.,0.));
#959=AXIS2_PLACEMENT_3D('',#956,#957,#958);
#960=CYLINDRICAL_SURFACE('',#959,2.6924);
#961=ORIENTED_EDGE('',*,*,#881,.T.);
#962=DIRECTION('',(0.,0.,-1.));
#963=VECTOR('',#962,1.);
#964=CARTESIAN_POINT('',(41.275,-15.3416,12.7));
#965=LINE('',#964,#963);
#966=EDGE_CURVE('E700',#604,#871,#965,.T.);
#967=ORIENTED_EDGE('',*,*,#966,.F.);
#968=ORIENTED_EDGE('',*,*,#605,.F.);
#969=ORIENTED_EDGE('',*,*,#949,.T.);
#970=EDGE_LOOP('',(#961,#967,#968,#969));
#971=FACE_BOUND('',#970,.T.);
#972=ADVANCED_FACE('F447',(#971),#960,.T.);
#973=CARTESIAN_POINT('',(41.275,-15.3416,12.7));
#974=DIRECTION('',(-1.,0.,0.));
#975=DIRECTION('',(0.,0.,1.));
#976=AXIS2_PLACEMENT_3D('',#973,#974,#975);
#977=PLANE('',#976);
#978=ORIENTED_EDGE('',*,*,#872,.T.);
#979=DIRECTION('',(0.,0.,-1.));
#980=VECTOR('',#979,1.);
#981=CARTESIAN_POINT('',(41.275,18.4785,12.7));
#982=LINE('',#981,#980);
#983=EDGE_CURVE('E697',#612,#863,#982,.T.);
#984=ORIENTED_EDGE('',*,*,#983,.F.);
#985=ORIENTED_EDGE('',*,*,#613,.F.);
#986=ORIENTED_EDGE('',*,*,#966,.T.);
#987=EDGE_LOOP('',(#978,#984,#985,#986));
#988=FACE_BOUND('',#987,.T.);
#989=ADVANCED_FACE('F457',(#988),#977,.F.);
#990=CARTESIAN_POINT('',(36.5125,18.4785,12.7));
#991=DIRECTION('',(0.,0.,-1.));
#992=DIRECTION('',(-1.,0.,0.));
#993=AXIS2_PLACEMENT_3D('',#990,#991,#992);
#994=CYLINDRICAL_SURFACE('',#993,4.7625);
#995=ORIENTED_EDGE('',*,*,#864,.T.);
#996=DIRECTION('',(0.,0.,-1.));
#997=VECTOR('',#996,1.);
#998=CARTESIAN_POINT('',(31.75,18.4785,12.7));
#999=LINE('',#998,#997);
#1000=EDGE_CURVE('E694',#621,#854,#999,.T.);
#1001=ORIENTED_EDGE('',*,*,#1000,.F.);
#1002=ORIENTED_EDGE('',*,*,#622,.F.);
#1003=ORIENTED_EDGE('',*,*,#983,.T.);
#1004=EDGE_LOOP('',(#995,#1001,#1002,#1003));
#1005=FACE_BOUND('',#1004,.T.);
#1006=ADVANCED_FACE('F467',(#1005),#994,.T.);
#1007=CARTESIAN_POINT('',(31.75,18.4785,12.7));
#1008=DIRECTION('',(1.,0.,0.));
#1009=DIRECTION('',(0.,1.,0.));
#1010=AXIS2_PLACEMENT_3D('',#1007,#1008,#1009);
#1011=PLANE('',#1010);
#1012=ORIENTED_EDGE('',*,*,#855,.T.);
#1013=DIRECTION('',(0.,0.,-1.));
#1014=VECTOR('',#1013,1.);
#1015=CARTESIAN_POINT('',(31.75,17.44345,12.7));
#1016=LINE('',#1015,#1014);
#1017=EDGE_CURVE('E691',#629,#846,#1016,.T.);
#1018=ORIENTED_EDGE('',*,*,#1017,.F.);
#1019=ORIENTED_EDGE('',*,*,#630,.F.);
#1020=ORIENTED_EDGE('',*,*,#1000,.T.);
#1021=EDGE_LOOP('',(#1012,#1018,#1019,#1020));
#1022=FACE_BOUND('',#1021,.T.);
#1023=ADVANCED_FACE('F477',(#1022),#1011,.F.);
#1024=CARTESIAN_POINT('',(33.0962,17.44345,12.7));
#1025=DIRECTION('',(0.,0.,-1.));
#1026=DIRECTION('',(-1.,0.,0.));
#1027=AXIS2_PLACEMENT_3D('',#1024,#1025,#1026);
#1028=CYLINDRICAL_SURFACE('',#1027,1.3462);
#1029=ORIENTED_EDGE('',*,*,#847,.T.);
#1030=DIRECTION('',(0.,0.,-1.));
#1031=VECTOR('',#1030,1.);
#1032=CARTESIAN_POINT('',(34.4424,17.44345,12.7));
#1033=LINE('',#1032,#1031);
#1034=EDGE_CURVE('E688',#638,#837,#1033,.T.);
#1035=ORIENTED_EDGE('',*,*,#1034,.F.);
#1036=ORIENTED_EDGE('',*,*,#639,.F.);
#1037=ORIENTED_EDGE('',*,*,#1017,.T.);
#1038=EDGE_LOOP('',(#1029,#1035,#1036,#1037));
#1039=FACE_BOUND('',#1038,.T.);
#1040=ADVANCED_FACE('F487',(#1039),#1028,.T.);
#1041=CARTESIAN_POINT('',(34.4424,18.4785,12.7));
#1042=DIRECTION('',(-1.,0.,0.));
#1043=DIRECTION('',(0.,0.,1.));
#1044=AXIS2_PLACEMENT_3D('',#1041,#1042,#1043);
#1045=PLANE('',#1044);
#1046=ORIENTED_EDGE('',*,*,#838,.T.);
#1047=DIRECTION('',(0.,0.,-1.));
#1048=VECTOR('',#1047,1.);
#1049=CARTESIAN_POINT('',(34.4424,18.4785,12.7));
#1050=LINE('',#1049,#1048);
#1051=EDGE_CURVE('E685',#646,#829,#1050,.T.);
#1052=ORIENTED_EDGE('',*,*,#1051,.F.);
#1053=ORIENTED_EDGE('',*,*,#647,.F.);
#1054=ORIENTED_EDGE('',*,*,#1034,.T.);
#1055=EDGE_LOOP('',(#1046,#1052,#1053,#1054));
#1056=FACE_BOUND('',#1055,.T.);
#1057=ADVANCED_FACE('F497',(#1056),#1045,.F.);
#1058=CARTESIAN_POINT('',(36.5125,18.4785,12.7));
#1059=DIRECTION('',(0.,0.,-1.));
#1060=DIRECTION('',(-1.,0.,0.));
#1061=AXIS2_PLACEMENT_3D('',#1058,#1059,#1060);
#1062=CYLINDRICAL_SURFACE('',#1061,2.0701);
#1063=ORIENTED_EDGE('',*,*,#830,.T.);
#1064=DIRECTION('',(0.,0.,-1.));
#1065=VECTOR('',#1064,1.);
#1066=CARTESIAN_POINT('',(38.5826,18.4785,12.7));
#1067=LINE('',#1066,#1065);
#1068=EDGE_CURVE('E682',#655,#820,#1067,.T.);
#1069=ORIENTED_EDGE('',*,*,#1068,.F.);
#1070=ORIENTED_EDGE('',*,*,#656,.F.);
#1071=ORIENTED_EDGE('',*,*,#1051,.T.);
#1072=EDGE_LOOP('',(#1063,#1069,#1070,#1071));
#1073=FACE_BOUND('',#1072,.T.);
#1074=ADVANCED_FACE('F507',(#1073),#1062,.F.);
#1075=CARTESIAN_POINT('',(38.5826,-15.3416,12.7));
#1076=DIRECTION('',(1.,0.,0.));
#1077=DIRECTION('',(0.,0.,-1.));
#1078=AXIS2_PLACEMENT_3D('',#1075,#1076,#1077);
#1079=PLANE('',#1078);
#1080=ORIENTED_EDGE('',*,*,#821,.T.);
#1081=DIRECTION('',(0.,0.,-1.));
#1082=VECTOR('',#1081,1.);
#1083=CARTESIAN_POINT('',(38.5826,-15.3416,12.7));
#1084=LINE('',#1083,#1082);
#1085=EDGE_CURVE('E679',#663,#812,#1084,.T.);
#1086=ORIENTED_EDGE('',*,*,#1085,.F.);
#1087=ORIENTED_EDGE('',*,*,#664,.F.);
#1088=ORIENTED_EDGE('',*,*,#1068,.T.);
#1089=EDGE_LOOP('',(#1080,#1086,#1087,#1088));
#1090=FACE_BOUND('',#1089,.T.);
#1091=ADVANCED_FACE('F517',(#1090),#1079,.F.);
#1092=CARTESIAN_POINT('',(2.6924,-15.3416,12.7));
#1093=DIRECTION('',(0.,-1.,0.));
#1094=DIRECTION('',(0.,0.,-1.));
#1095=AXIS2_PLACEMENT_3D('',#1092,#1093,#1094);
#1096=PLANE('',#1095);
#1097=ORIENTED_EDGE('',*,*,#813,.T.);
#1098=DIRECTION('',(0.,0.,-1.));
#1099=VECTOR('',#1098,1.);
#1100=CARTESIAN_POINT('',(2.6924,-15.3416,12.7));
#1101=LINE('',#1100,#1099);
#1102=EDGE_CURVE('E676',#671,#804,#1101,.T.);
#1103=ORIENTED_EDGE('',*,*,#1102,.F.);
#1104=ORIENTED_EDGE('',*,*,#672,.F.);
#1105=ORIENTED_EDGE('',*,*,#1085,.T.);
#1106=EDGE_LOOP('',(#1097,#1103,#1104,#1105));
#1107=FACE_BOUND('',#1106,.T.);
#1108=ADVANCED_FACE('F527',(#1107),#1096,.F.);
#1109=CARTESIAN_POINT('',(2.69239999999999,18.4785,12.7));
#1110=DIRECTION('',(-1.,0.,0.));
#1111=DIRECTION('',(0.,-1.,0.));
#1112=AXIS2_PLACEMENT_3D('',#1109,#1110,#1111);
#1113=PLANE('',#1112);
#1114=ORIENTED_EDGE('',*,*,#805,.T.);
#1115=DIRECTION('',(0.,0.,-1.));
#1116=VECTOR('',#1115,1.);
#1117=CARTESIAN_POINT('',(2.69239999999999,18.4785,12.7));
#1118=LINE('',#1117,#1116);
#1119=EDGE_CURVE('E673',#679,#796,#1118,.T.);
#1120=ORIENTED_EDGE('',*,*,#1119,.F.);
#1121=ORIENTED_EDGE('',*,*,#680,.F.);
#1122=ORIENTED_EDGE('',*,*,#1102,.T.);
#1123=EDGE_LOOP('',(#1114,#1120,#1121,#1122));
#1124=FACE_BOUND('',#1123,.T.);
#1125=ADVANCED_FACE('F537',(#1124),#1113,.F.);
#1126=CARTESIAN_POINT('',(4.7625,18.4785,12.7));
#1127=DIRECTION('',(0.,0.,-1.));
#1128=DIRECTION('',(-1.,0.,0.));
#1129=AXIS2_PLACEMENT_3D('',#1126,#1127,#1128);
#1130=CYLINDRICAL_SURFACE('',#1129,2.07010000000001);
#1131=ORIENTED_EDGE('',*,*,#797,.T.);
#1132=DIRECTION('',(0.,0.,-1.));
#1133=VECTOR('',#1132,1.);
#1134=CARTESIAN_POINT('',(6.8326,18.4785,12.7));
#1135=LINE('',#1134,#1133);
#1136=EDGE_CURVE('E670',#688,#787,#1135,.T.);
#1137=ORIENTED_EDGE('',*,*,#1136,.F.);
#1138=ORIENTED_EDGE('',*,*,#689,.F.);
#1139=ORIENTED_EDGE('',*,*,#1119,.T.);
#1140=EDGE_LOOP('',(#1131,#1137,#1138,#1139));
#1141=FACE_BOUND('',#1140,.T.);
#1142=ADVANCED_FACE('F547',(#1141),#1130,.F.);
#1143=CARTESIAN_POINT('',(6.8326,18.4785,12.7));
#1144=DIRECTION('',(1.,0.,0.));
#1145=DIRECTION('',(0.,0.,-1.));
#1146=AXIS2_PLACEMENT_3D('',#1143,#1144,#1145);
#1147=PLANE('',#1146);
#1148=ORIENTED_EDGE('',*,*,#788,.T.);
#1149=DIRECTION('',(0.,0.,-1.));
#1150=VECTOR('',#1149,1.);
#1151=CARTESIAN_POINT('',(6.8326,17.44345,12.7));
#1152=LINE('',#1151,#1150);
#1153=EDGE_CURVE('E667',#696,#779,#1152,.T.);
#1154=ORIENTED_EDGE('',*,*,#1153,.F.);
#1155=ORIENTED_EDGE('',*,*,#697,.F.);
#1156=ORIENTED_EDGE('',*,*,#1136,.T.);
#1157=EDGE_LOOP('',(#1148,#1154,#1155,#1156));
#1158=FACE_BOUND('',#1157,.T.);
#1159=ADVANCED_FACE('F557',(#1158),#1147,.F.);
#1160=CARTESIAN_POINT('',(8.1788,17.44345,12.7));
#1161=DIRECTION('',(0.,0.,-1.));
#1162=DIRECTION('',(-1.,0.,0.));
#1163=AXIS2_PLACEMENT_3D('',#1160,#1161,#1162);
#1164=CYLINDRICAL_SURFACE('',#1163,1.3462);
#1165=ORIENTED_EDGE('',*,*,#780,.T.);
#1166=DIRECTION('',(0.,0.,-1.));
#1167=VECTOR('',#1166,1.);
#1168=CARTESIAN_POINT('',(9.525,17.44345,12.7));
#1169=LINE('',#1168,#1167);
#1170=EDGE_CURVE('E602',#705,#770,#1169,.T.);
#1171=ORIENTED_EDGE('',*,*,#1170,.F.);
#1172=ORIENTED_EDGE('',*,*,#706,.F.);
#1173=ORIENTED_EDGE('',*,*,#1153,.T.);
#1174=EDGE_LOOP('',(#1165,#1171,#1172,#1173));
#1175=FACE_BOUND('',#1174,.T.);
#1176=ADVANCED_FACE('F567',(#1175),#1164,.T.);
#1177=CARTESIAN_POINT('',(9.525,18.4785,12.7));
#1178=DIRECTION('',(-1.,0.,0.));
#1179=DIRECTION('',(0.,0.,1.));
#1180=AXIS2_PLACEMENT_3D('',#1177,#1178,#1179);
#1181=PLANE('',#1180);
#1182=ORIENTED_EDGE('',*,*,#771,.T.);
#1183=ORIENTED_EDGE('',*,*,#917,.F.);
#1184=ORIENTED_EDGE('',*,*,#714,.F.);
#1185=ORIENTED_EDGE('',*,*,#1170,.T.);
#1186=EDGE_LOOP('',(#1182,#1183,#1184,#1185));
#1187=FACE_BOUND('',#1186,.T.);
#1188=ADVANCED_FACE('F577',(#1187),#1181,.F.);
#1189=CLOSED_SHELL('',(#60,#91,#124,#155,#188,#230,#261,#294,#325,#358,#389,#420,#451,#484,#515,
#548,#570,#737,#904,#921,#938,#955,#972,#989,#1006,#1023,#1040,#1057,#1074,#1091,#1108,#1125,
#1142,#1159,#1176,#1188));
#1190=MANIFOLD_SOLID_BREP('B2',#1189);
#1191=ADVANCED_BREP_SHAPE_REPRESENTATION('',(#18,#1190),#14);
#1192=SHAPE_DEFINITION_REPRESENTATION(#9,#1191);
ENDSEC;
END-ISO-10303-21;
